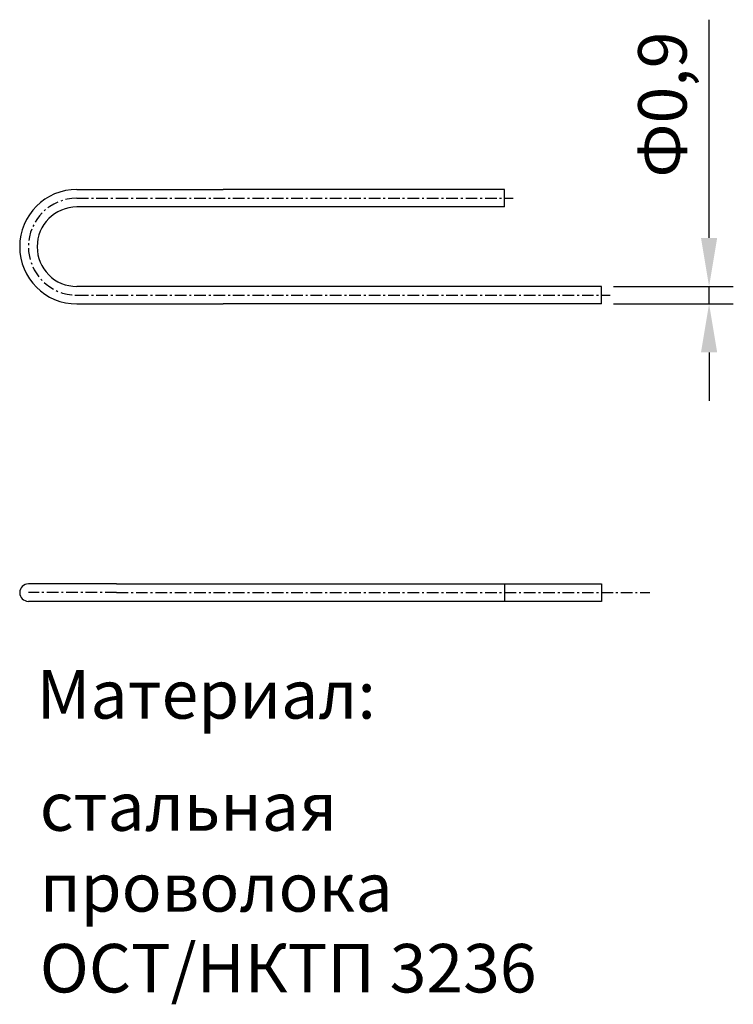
# Model space of a CAD drawing. Units: millimetres. Extents: x -14 to 22.8, y 121.6 to 172.4.
import ezdxf

# ---------------------------------------------------------------- set-up
doc = ezdxf.new("R2010")
doc.units = ezdxf.units.MM
doc.header["$LTSCALE"] = 0.2
doc.linetypes.add('ACAD_ISO10W100', pattern=[18, 12, -3, 0, -3])
doc.dimstyles.new('ISO-25', dxfattribs={"dimtxt": 2.5, "dimasz": 2.5, "dimexe": 1.25, "dimexo": 0.625, "dimtad": 1, "dimtxsty": 'Standard', "dimcen": 2.5, "dimadec": 0, "dimazin": 0, "dimtfac": 1, "dimtmove": 0, "dimatfit": 3, "dimfxl": 0, "dimarcsym": 0})

# ---------------------------------------------------------------- blocks, each defined once
blk = doc.blocks.new('*D2')
at = {"color": 0, "lineweight": -2, "ltscale": 0.25}
for p, q in [((21.552, 161.102), (21.552, 172.352)), ((16.625, 158.602), (22.802, 158.602)), ((21.552, 157.702), (21.552, 158.602)), ((16.625, 157.702), (22.802, 157.702)), ((21.552, 155.202), (21.552, 152.702))]:
    blk.add_line(p, q, dxfattribs=at)
at = {"color": 0, "lineweight": 15, "ltscale": 0.25}
for points in [[(21.136, 161.102), (21.969, 161.102), (21.552, 158.602)], [(21.136, 155.202), (21.969, 155.202), (21.552, 157.702)]]:
    blk.add_solid(points, dxfattribs=at)
at = {"layer": 'Defpoints', "color": 0, "lineweight": 15, "ltscale": 0.25}
for p in [(16, 158.602), (21.552, 158.602), (16, 157.702)]:
    blk.add_point(p, dxfattribs=at)
at = {"color": 0, "lineweight": 15, "ltscale": 0.25, "insert": (19.469, 167.977), "char_height": 2.5, "attachment_point": 5, "rotation": 90}
blk.add_mtext('Ф0,9', dxfattribs=at)

msp = doc.modelspace()

# ---------------------------------------------------------------- linework, layer by layer
at = {"color": 7, "lineweight": 30, "ltscale": 0.25}
for p, q in [((-11.05, 163.602), (-3.5, 163.602)), ((11, 163.602), (-3.5, 163.602)), ((11, 162.702), (11, 163.602)), ((-3.5, 162.702), (-11.05, 162.702)), ((11, 162.702), (-3.5, 162.702)), ((-3.5, 158.602), (-11.05, 158.602)), ((16, 158.602), (-3.5, 158.602)), ((16, 157.702), (16, 158.602)), ((-11.05, 157.702), (-3.5, 157.702)), ((16, 157.702), (-3.5, 157.702)), ((-9, 143.273), (-13.55, 143.273)), ((-9, 143.273), (11, 143.273)), ((11, 143.273), (11, 142.373)), ((11, 143.273), (16, 143.273)), ((16, 143.273), (16, 142.373)), ((-9, 142.373), (-13.55, 142.373)), ((11, 142.373), (-9, 142.373)), ((16, 142.373), (11, 142.373))]:
    msp.add_line(p, q, dxfattribs=at)
at = {"color": 1, "linetype": 'ACAD_ISO10W100', "lineweight": 25, "ltscale": 0.25}
for p, q in [((-11.05, 163.152), (-9, 163.152)), ((-9, 163.152), (11.45, 163.152)), ((-11.05, 158.152), (-9, 158.152)), ((-9, 158.152), (16.45, 158.152)), ((-9, 142.823), (-13.55, 142.823)), ((-9, 142.823), (18.492, 142.823))]:
    msp.add_line(p, q, dxfattribs=at)
at = {"color": 7, "lineweight": 30, "ltscale": 0.25}
for centre, radius in [((-11.05, 160.652), 2.95), ((-11.05, 160.652), 2.05), ((-13.55, 142.823), 0.45)]:
    msp.add_arc(centre, radius, 90, 270, dxfattribs=at)
at = {"color": 1, "linetype": 'ACAD_ISO10W100', "lineweight": 25, "ltscale": 0.25}
msp.add_arc((-11.05, 160.652), 2.5, 90, 270, dxfattribs=at)

# ---------------------------------------------------------------- texts
at = {"color": 7, "lineweight": 15, "ltscale": 0.25}
for s, p in [('Материал:', (-13.123, 136.328)), ('стальная', (-12.963, 130.548)), ('проволока', (-12.963, 126.382)), ('ОСТ/НКТП 3236', (-12.963, 122.215))]:
    msp.add_text(s, height=2.5, dxfattribs=at).set_placement(p)

# ---------------------------------------------------------------- dimensions: what is measured, and where the dimension line sits
at = {"color": 3, "lineweight": 15, "ltscale": 0.25}
dim = msp.add_linear_dim(base=(21.552, 158.602), p1=(16, 157.702), p2=(16, 158.602), angle=90, text='Ф0,9', dimstyle='ISO-25', dxfattribs=at)
dim.commit()
dim.dimension.update_dxf_attribs({"geometry": '*D2', "text_midpoint": (19.469, 167.977)})

doc.saveas('drawing.dxf')
